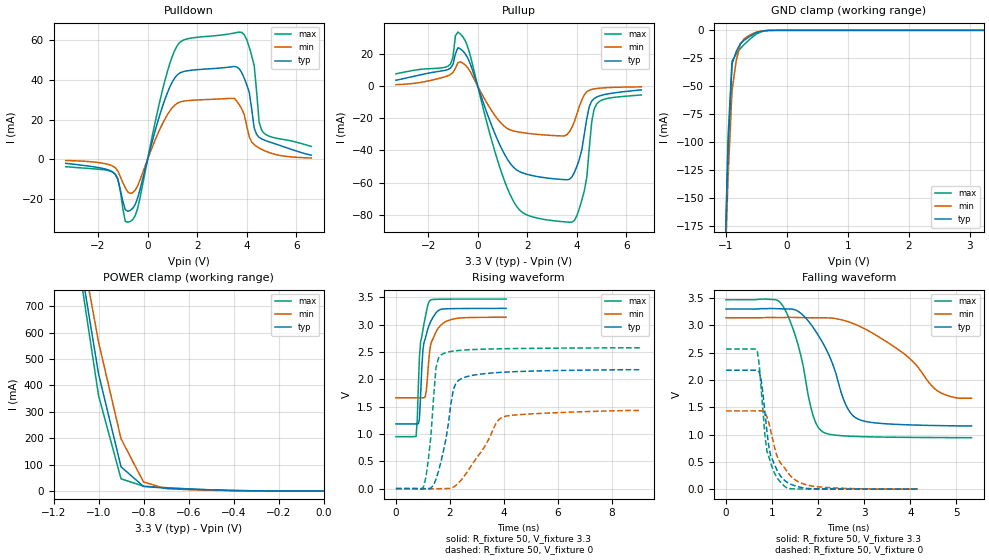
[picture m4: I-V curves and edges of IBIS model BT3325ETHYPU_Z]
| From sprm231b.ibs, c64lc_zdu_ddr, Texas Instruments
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|   Model Cell BT3325ETHYPUFZSCP18
[Model]   BT3325ETHYPU_Z
Model_type   I/O
Polarity   Non-Inverting
Enable   Active-Low
Vinl =  0.8V
Vinh =  2V
Cref =  15.0000pF
Rref =  100.0000M
Vref =  0V
Vmeas =  1.65
C_comp   2.566034p   2.494321p   2.623693p
[Model Spec]
Vinl   0.8V   0.8V   0.8V
Vinh   2V   2V   2V
[Temperature Range]   25   125   -40
[Voltage Range]   3.3   3.14   3.47
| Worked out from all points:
|   slope of the pulldown table from 0 to 0.495 V, typ, clamps not added: 22 ohm
|   slope of the pullup table from 0 to 0.495 V, typ, clamps not added: 22.7 ohm
|   GND clamp passes 1 mA (typ) near -0.43 V on its own axis
|   POWER clamp passes 1 mA (typ) near -0.34 V on its own axis
|   rising waveform, R_fixture 50, V_fixture 3.3: 20-80 % time 251ps typ, 305ps min, 218ps max; typ from 1.18 V to 3.3 V
|   rising waveform, R_fixture 50, V_fixture 0: 20-80 % time 464ps typ, 1.04ns min, 263ps max; typ from 0 V to 2.18 V
|   falling waveform, R_fixture 50, V_fixture 3.3: 20-80 % time 617ps typ, 1.19ns min, 415ps max; typ from 3.3 V to 1.16 V
|   falling waveform, R_fixture 50, V_fixture 0: 20-80 % time 257ps typ, 407ps min, 215ps max; typ from 2.18 V to 0.001 V
[POWER_clamp]
|   voltage   I(typ)   I(min)   I(max)
-3.3V     15.08A     13.67A     16.19A
-1.067V   791.8mA    876.7mA    739.6mA
-1.033V   617.9mA    720.5mA    550.7mA
-1V       443.9mA    564.3mA    361.8mA
-900mV    91.43mA    197.6mA    46.01mA
-800mV    17.02mA    33.96mA    17.85mA
-700mV    10.54mA    8.637mA    12.45mA
-400mV    1.692mA    1.038mA    1.485mA
-11.55fV  124.8nA    283.5nA    244.8nA
[Pulldown]
|   voltage   I(typ)   I(min)   I(max)
-3.3V     -2.009mA   -598.7uA   -3.704mA
-1.4V     -6.443mA   -3.405mA   -6.53mA
-900mV    -25.27mA   -14.31mA   -31.18mA
-600mV    -24.63mA   -16.76mA   -30.27mA
700mV     30.19mA    20.31mA    39.68mA
1.2V      42.48mA    28.23mA    57.23mA
3.7V      45.45mA    27.48mA    63.96mA
4.1V      33.69mA    11.27mA    56.39mA
4.3V      15.66mA    7.38mA     47.1mA
4.5V      11.07mA    5.671mA    18.53mA
4.6V      10.27mA    5.02mA     14.66mA
6.6V      2.127mA    698uA      6.501mA
[Pullup]
|   voltage   I(typ)   I(min)   I(max)
-3.3V     3.672mA    942uA      7.701mA
-1.2V     10.36mA    6.515mA    12.43mA
-900mV    20.11mA    11.14mA    31.42mA
-700mV    23.22mA    15.14mA    32.51mA
1.4V      -49.76mA   -27.7mA    -70.44mA
3.4V      -58.08mA   -30.96mA   -84.31mA
4.1V      -45.46mA   -12.4mA    -76.1mA
4.4V      -20.13mA   -3.457mA   -56.69mA
4.5V      -12.6mA    -2.531mA   -38.48mA
4.6V      -9.27mA    -2.014mA   -21.88mA
4.8V      -6.737mA   -1.451mA   -11.02mA
6.6V      -2.305mA   -414.2uA   -5.467mA
[GND_clamp]
|   voltage   I(typ)   I(min)   I(max)
-3.3V     -17.31A    -15.67A    -18.52A
-1.033V   -242.4mA   -247.8mA   -249mA
-966.7mV  -107.5mA   -133.2mA   -96.03mA
-900mV    -30.1mA    -53.58mA   -27.5mA
-833.3mV  -19.23mA   -27.87mA   -21.45mA
-766.7mV  -12.15mA   -12.5mA    -16.49mA
-700mV    -8.877mA   -7.487mA   -12.64mA
-566.7mV  -4.001mA   -3.142mA   -6.073mA
-500mV    -2.028mA   -1.615mA   -3.281mA
-433.3mV  -975.8uA   -827.9uA   -1.629mA
-300mV    -52.39uA   -75.47uA   -82.68uA
3.233V    68.23nA    4.314uA    201.3nA
[Ramp]
| variable   typ   min   max
dV/dt_f   1.303669/0.626078n   0.9851965/1.278608n   1.530191/0.4190725n
dV/dt_r   1.326854/0.4645258n  0.9114419/1.09422n   1.556718/0.2523652n
R_load = 50
[Rising Waveform]
R_fixture = 50
V_fixture = 3.3
V_fixture_min = 3.14
V_fixture_max = 3.47
|   time   V(typ)   V(min)   V(max)
0s        1.183V     1.662V     951mV
748ps     1.185V     1.663V     955.3mV
792ps     1.185V     1.663V     1.275V
872ps     1.279V     1.664V     2.417V
916ps     1.714V     1.664V     2.694V
1ns       2.535V     1.663V     2.907V
1.124ns   2.817V     1.777V     3.227V
1.252ns   3.016V     2.527V     3.44V
1.876ns   3.292V     3.063V     3.469V
4.084ns   3.299V     3.137V     3.47V
[Rising Waveform]
R_fixture = 50
V_fixture = 0
V_fixture_min = 0
V_fixture_max = 0
|   time   V(typ)   V(min)   V(max)
0s        45.31uV    38.64uV    55.69uV
1.016ns   -6.992mV   17.43uV    21.41mV
1.112ns   -3.502mV   -2.537mV   207.8mV
1.296ns   9.616mV    -6.223mV   961.8mV
1.484ns   168.6mV    -2.402mV   2.211V
1.76ns    684.9mV    -53.96uV   2.473V
2.132ns   1.82V      27.37mV    2.518V
2.504ns   2.03V      210.4mV    2.536V
3.992ns   2.131V     1.314V     2.561V
9.096ns   2.176V     1.431V     2.578V
[Falling Waveform]
R_fixture = 50
V_fixture = 3.3
V_fixture_min = 3.14
V_fixture_max = 3.47
|   time   V(typ)   V(min)   V(max)
0s        3.3V       3.14V      3.47V
1.192ns   3.304V     3.143V     3.405V
1.572ns   3.253V     3.144V     2.619V
1.896ns   2.956V     3.141V     1.33V
2.116ns   2.655V     3.139V     1.041V
2.604ns   1.537V     3.079V     974.4mV
2.82ns    1.304V     3.013V     966.1mV
3.908ns   1.18V      2.45V      949.2mV
4.612ns   1.165V     1.788V     945.1mV
5.328ns   1.159V     1.665V     943.4mV
[Falling Waveform]
R_fixture = 50
V_fixture = 0
V_fixture_min = 0
V_fixture_max = 0
|   time   V(typ)   V(min)   V(max)
0s        2.18V      1.434V     2.567V
676ps     2.181V     1.434V     2.539V
760ps     2.015V     1.436V     1.867V
844ps     1.408V     1.399V     986.7mV
888ps     1.055V     1.328V     696.1mV
972ps     602mV      1.062V     472.7mV
1.1ns     359.9mV    624.7mV    221.2mV
1.272ns   160mV      388.9mV    51.79mV
1.864ns   8.981mV    58.08mV    1.916mV
4.168ns   936.9uV    3.182mV    81.56uV
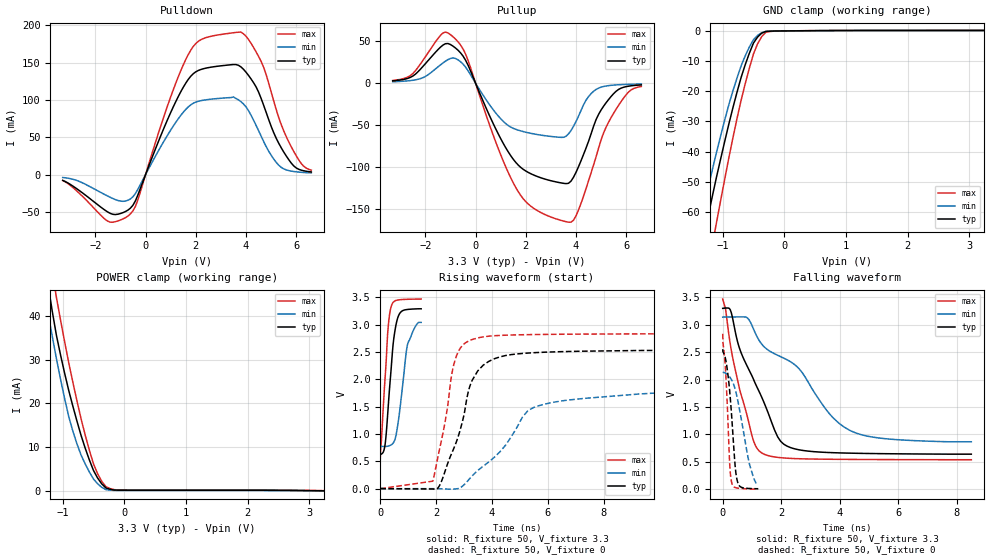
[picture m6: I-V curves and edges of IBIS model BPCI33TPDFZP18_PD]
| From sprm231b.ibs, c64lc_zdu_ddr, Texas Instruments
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|   Model Cell BPCI33TPDFZP18
[Model]   BPCI33TPDFZP18_PD
Model_type   I/O
Polarity   Non-Inverting
Enable   Active-Low
Vinl =  0.8
Vinh =  2.0
Cref =  10.0000pF
Rref =  50.0000
Vref =  1.5V
Vmeas =  1.5
C_comp   3.400798p   3.348868p   3.529696p
[Temperature Range]   25   125   -40
[Voltage Range]   3.3   3.14   3.47
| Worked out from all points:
|   slope of the pulldown table from 0 to 0.495 V, typ, clamps not added: 11.5 ohm
|   slope of the pullup table from 0 to 0.495 V, typ, clamps not added: 14.2 ohm
|   GND clamp passes 1 mA (typ) near -0.38 V on its own axis
|   POWER clamp passes 1 mA (typ) near -0.32 V on its own axis
|   rising waveform, R_fixture 50, V_fixture 3.3: 20-80 % time 251ps typ, 312ps min, 203ps max; typ from 0.618 V to 3.29 V
|   rising waveform, R_fixture 50, V_fixture 0: 20-80 % time 912ps typ, 3.25ns min, 574ps max; typ from 0 V to 2.55 V
|   falling waveform, R_fixture 50, V_fixture 3.3: 20-80 % time 1.24ns typ, 2.46ns min, 739ps max; typ from 3.3 V to 0.642 V
|   falling waveform, R_fixture 50, V_fixture 0: 20-80 % time 223ps typ, 423ps min, 145ps max; typ from 2.56 V to 0.011 V
[POWER_clamp]
|   voltage   I(typ)   I(min)   I(max)
-3.3V     267mA      206.5mA    325.9mA
-1.3V     53.32mA    45.7mA     64.06mA
-1.233V   46.92mA    40.45mA    56.76mA
-1.167V   41mA       35.29mA    50.15mA
-1.1V     35.56mA    30.24mA    44.25mA
-900mV    22.94mA    16.96mA    29.27mA
-700mV    12.65mA    8.17mA     16.44mA
-500mV    4.676mA    2.728mA    6.199mA
-366.7mV  1.613mA    815.6uA    2.199mA
-300mV    677.7uA    289.8uA    976.9uA
-100mV    146.2uA    88.28uA    203.6uA
3.233V    6.454uA    -18.59uA   49.21uA
[Pulldown]
|   voltage   I(typ)   I(min)   I(max)
-3.3V     -7.788mA   -3.889mA   -7.987mA
-1.5V     -50.3mA    -28.94mA   -62.59mA
-700mV    -47.57mA   -34.42mA   -55.53mA
-400mV    -34.9mA    -25.14mA   -42.3mA
900mV     75.57mA    54.22mA    94.65mA
1.8V      131.8mA    93.47mA    166.8mA
2.4V      142.6mA    100.2mA    183.5mA
3.8V      144.2mA    97.66mA    191mA
4.6V      102.2mA    51.63mA    151.8mA
5.3V      42.12mA    12.63mA    76.7mA
6.1V      7.063mA    3.322mA    19.68mA
6.6V      3.543mA    2.233mA    5.963mA
[Pullup]
|   voltage   I(typ)   I(min)   I(max)
-3.3V     2.841mA    1.735mA    3.327mA
-2.6V     6.94mA     3.146mA    9.053mA
-1.4V     43.04mA    21.89mA    57.16mA
-1V       46.23mA    29.6mA     58.04mA
-400mV    27.62mA    19.3mA     34.95mA
900mV     -60.4mA    -39.07mA   -77.82mA
1.7V      -97.84mA   -56.07mA   -129.6mA
3.7V      -119.6mA   -60.58mA   -166mA
4.1V      -99.72mA   -39.32mA   -151.4mA
5.2V      -23.22mA   -3.285mA   -52.37mA
6V        -4.027mA   -1.402mA   -13.57mA
6.6V      -2.032mA   -942.8uA   -3.85mA
[GND_clamp]
|   voltage   I(typ)   I(min)   I(max)
-3.3V     -301.2mA   -235.6mA   -364.4mA
-1.367V   -75.51mA   -63.63mA   -93.99mA
-1.3V     -68.15mA   -57.67mA   -85.99mA
-1.233V   -61.35mA   -51.8mA    -78.43mA
-1.1V     -48.52mA   -40.32mA   -63.59mA
-900mV    -30.93mA   -24.51mA   -42.17mA
-700mV    -15.41mA   -11.59mA   -22.96mA
-500mV    -4.036mA   -2.901mA   -7.657mA
-366.7mV  -757uA     -601.1uA   -1.906mA
-300mV    -173.8uA   -161.6uA   -469.5uA
-166.7mV  -45.04uA   -35.14uA   -70.3uA
3.233V    143uA      89.63uA    196.9uA
[Ramp]
| variable   typ   min   max
dV/dt_f   1.61157/1.246779n   1.412395/2.561021n   1.763671/0.7410372n
dV/dt_r   1.538377/0.9052153n   1.251512/3.825666n   1.705345/0.5758693n
R_load = 50
[Rising Waveform]
R_fixture = 50
V_fixture = 3.3
V_fixture_min = 3.14
V_fixture_max = 3.47
|   time   V(typ)   V(min)   V(max)
0s        617.6mV    771.4mV    534.9mV
8ps       625.1mV    771.6mV    684.2mV
176ps     820.5mV    771.5mV    2.052V
280ps     1.469V     777.4mV    2.937V
384ps     2.156V     798.4mV    3.319V
488ps     2.76V      854.5mV    3.419V
656ps     3.165V     1.268V     3.45V
976ps     3.276V     2.635V     3.462V
1.264ns   3.286V     2.971V     3.465V
1.464ns   3.288V     3.039V     3.466V
[Rising Waveform]
R_fixture = 50
V_fixture = 0
V_fixture_min = 0
V_fixture_max = 0
|   time   V(typ)   V(min)   V(max)
0s        22.7uV     15.94uV    32.12uV
1.88ns    -6.279mV   -641.8uV   136.8mV
2.12ns    55.12mV    -1.771mV   715.9mV
2.672ns   785.6mV    -5.519mV   2.342V
3.184ns   1.834V     172.6mV    2.704V
3.488ns   2.151V     331.2mV    2.756V
4.488ns   2.434V     796.2mV    2.805V
5.288ns   2.479V     1.428V     2.815V
6.496ns   2.504V     1.604V     2.823V
26.97ns   2.552V     2.038V     2.835V
[Falling Waveform]
R_fixture = 50
V_fixture = 3.3
V_fixture_min = 3.14
V_fixture_max = 3.47
|   time   V(typ)   V(min)   V(max)
0s        3.298V     3.139V     3.468V
96ps      3.305V     3.141V     3.293V
264ps     3.266V     3.141V     2.629V
568ps     2.582V     3.144V     1.846V
1.056ns   2.002V     2.92V      881.9mV
1.328ns   1.687V     2.652V     666.3mV
2.088ns   823.7mV    2.392V     572mV
2.616ns   720.2mV    2.196V     558.1mV
4.36ns    659.7mV    1.071V     545.7mV
8.504ns   641.6mV    867.6mV    539.9mV
[Falling Waveform]
R_fixture = 50
V_fixture = 0
V_fixture_min = 0
V_fixture_max = 0
|   time   V(typ)   V(min)   V(max)
0s        2.555V     2.134V     2.835V
8ps       2.507V     2.133V     2.668V
88ps      2.398V     2.12V      2.24V
160ps     2.168V     2.095V     1.495V
240ps     1.781V     2.049V     454.5mV
304ps     1.351V     1.995V     132mV
424ps     434.4mV    1.827V     33.66mV
520ps     116mV      1.607V     21.52mV
912ps     16.25mV    467.6mV    7.166mV
1.216ns   11.47mV    102.8mV    3.42mV
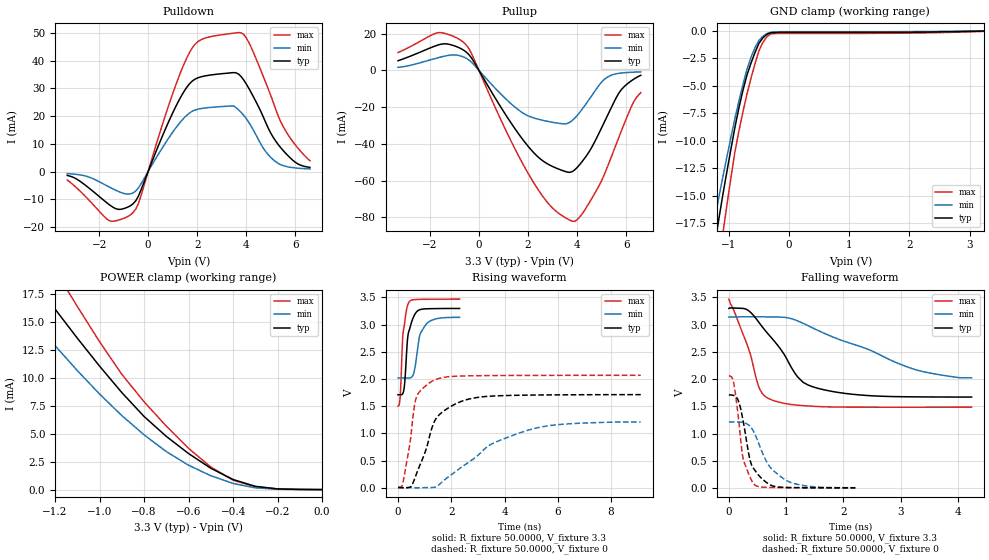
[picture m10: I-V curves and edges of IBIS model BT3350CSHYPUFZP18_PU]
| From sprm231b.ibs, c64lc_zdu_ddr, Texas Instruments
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|   Model Cell BT3350CSHYPUFZP18
[Model]   BT3350CSHYPUFZP18_PU
Model_type   I/O
Polarity   Non-Inverting
Enable   Active-Low
Vinl =  0.8V
Vinh =  2V
Cref =  15.0000pF
Rref =  100.0000M
Vref =  0V
Vmeas =  1.65
C_comp   1.705749p   1.660791p   1.75003p
[Model Spec]
Vinl   0.8V   0.8V   0.8V
Vinh   2V   2V   2V
[Temperature Range]   25   125   -40
[Voltage Range]   3.3   3.14   3.47
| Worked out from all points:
|   slope of the pulldown table from 0 to 0.495 V, typ, clamps not added: 45.1 ohm
|   slope of the pullup table from 0 to 0.495 V, typ, clamps not added: 43.8 ohm
|   GND clamp passes 1 mA (typ) near -0.48 V on its own axis
|   POWER clamp passes 1 mA (typ) near -0.41 V on its own axis
|   rising waveform, R_fixture 50.0000, V_fixture 3.3: 20-80 % time 204ps typ, 282ps min, 155ps max; typ from 1.71 V to 3.3 V
|   rising waveform, R_fixture 50.0000, V_fixture 0: 20-80 % time 850ps typ, 2.32ns min, 380ps max; typ from 0.003 V to 1.71 V
|   falling waveform, R_fixture 50.0000, V_fixture 3.3: 20-80 % time 671ps typ, 1.55ns min, 359ps max; typ from 3.3 V to 1.67 V
|   falling waveform, R_fixture 50.0000, V_fixture 0: 20-80 % time 218ps typ, 400ps min, 164ps max; typ from 1.71 V to 0.006 V
[POWER_clamp]
|   voltage   I(typ)   I(min)   I(max)
-3.3V     84.32mA    63.21mA    102.6mA
-1.4V     21.71mA    17.52mA    26.37mA
-1.367V   20.75mA    16.74mA    25.23mA
-1.233V   17.03mA    13.62mA    20.73mA
-1.133V   14.39mA    11.37mA    17.45mA
-900mV    8.665mA    6.611mA    10.3mA
-800mV    6.531mA    4.891mA    7.85mA
-600mV    3.22mA     2.176mA    3.684mA
-500mV    1.907mA    1.239mA    2.016mA
-400mV    899.8uA    551.4uA    840.8uA
-300mV    293.2uA    156uA      256.6uA
0V        111.9nA    201.5nA    235.4nA
[Pulldown]
|   voltage   I(typ)   I(min)   I(max)
-3.3V     -1.414mA   -745.4uA   -3.05mA
-1.6V     -11.86mA   -5.525mA   -17.66mA
-700mV    -12.23mA   -8.019mA   -15.5mA
-400mV    -8.953mA   -5.978mA   -11.65mA
900mV     19.23mA    12.9mA     25.53mA
1.7V      31.81mA    21.22mA    43.17mA
2.2V      34.3mA     22.8mA     47.78mA
3.7V      35.12mA    22.19mA    50.19mA
4.1V      30.16mA    17.85mA    46.74mA
5.1V      12.38mA    4.294mA    25.08mA
5.7V      5.756mA    1.687mA    13.38mA
6.6V      1.491mA    938uA      3.886mA
[Pullup]
|   voltage   I(typ)   I(min)   I(max)
-3.3V     5.279mA    1.68mA     9.743mA
-1.7V     13.72mA    6.799mA    20.48mA
-600mV    10.83mA    7.151mA    14.99mA
1.3V      -28.42mA   -18.04mA   -38.22mA
2.2V      -44.3mA    -25.71mA   -60.41mA
3V        -52.29mA   -28.23mA   -74.9mA
3.8V      -55.14mA   -27.3mA    -82.11mA
4.3V      -48.01mA   -19.44mA   -76.32mA
5.2V      -25.74mA   -3.981mA   -53.86mA
5.8V      -10.57mA   -1.414mA   -33.26mA
6.3V      -4.87mA    -940.5uA   -17.38mA
6.6V      -2.661mA   -794.2uA   -12.11mA
[GND_clamp]
|   voltage   I(typ)   I(min)   I(max)
-3.3V     -100.5mA   -76.68mA   -120mA
-1.3V     -21.87mA   -18.97mA   -26.4mA
-1.233V   -19.47mA   -17.07mA   -23.74mA
-1.167V   -17.17mA   -15.19mA   -21.1mA
-1.1V     -14.95mA   -13.32mA   -18.48mA
-1.033V   -12.86mA   -11.51mA   -15.92mA
-900mV    -8.833mA   -8.012mA   -11.06mA
-700mV    -4.051mA   -3.523mA   -5.792mA
-500mV    -1.133mA   -857.3uA   -1.811mA
-366.7mV  -308.6uA   -237uA     -524.5uA
-166.7mV  -140.1uA   -73.15uA   -228.2uA
3.233V    -8.683uA   9.95uA     -45.02uA
[Ramp]
| variable   typ   min   max
dV/dt_f  0.9828108/0.6678639n  0.7311943/1.730842n   1.197706/0.3608563n
dV/dt_r   1.030688/0.8545153n  0.7443786/2.444011n   1.242133/0.3789795n
R_load = 50
[Rising Waveform]
R_fixture = 50.0000
V_fixture = 3.3
V_fixture_min = 3.14
V_fixture_max = 3.47
|   time   V(typ)   V(min)   V(max)
0s        1.71V      2.018V     1.5V
80ps      1.71V      2.019V     1.671V
168ps     1.724V     2.019V     2.701V
224ps     1.815V     2.019V     2.953V
352ps     2.709V     2.019V     3.343V
400ps     2.867V     2.019V     3.405V
592ps     3.152V     2.111V     3.459V
800ps     3.271V     2.766V     3.464V
1.04ns    3.29V      2.997V     3.466V
2.312ns   3.298V     3.134V     3.469V
[Rising Waveform]
R_fixture = 50.0000
V_fixture = 0
V_fixture_min = 0
V_fixture_max = 0
|   time   V(typ)   V(min)   V(max)
0s        3.179mV    1.918mV    4.458mV
200ps     -2.005mV   1.924mV    130.7mV
496ps     27mV       627.6uV    1.01V
672ps     229.1mV    -2.315mV   1.638V
1.36ns    1.211V     7.009mV    1.979V
1.728ns   1.415V     136.8mV    2.03V
2.552ns   1.616V     434.7mV    2.057V
3.512ns   1.685V     804.2mV    2.063V
4.736ns   1.702V     1.036V     2.066V
9.12ns    1.712V     1.208V     2.068V
[Falling Waveform]
R_fixture = 50.0000
V_fixture = 3.3
V_fixture_min = 3.14
V_fixture_max = 3.47
|   time   V(typ)   V(min)   V(max)
0s        3.3V       3.14V      3.47V
352ps     3.252V     3.145V     2.534V
536ps     3.027V     3.145V     1.825V
712ps     2.798V     3.143V     1.636V
920ps     2.528V     3.139V     1.568V
1.2ns     2.044V     3.071V     1.523V
1.48ns    1.855V     2.933V     1.502V
2.224ns   1.717V     2.625V     1.487V
3.208ns   1.676V     2.191V     1.486V
4.24ns    1.672V     2.026V     1.487V
[Falling Waveform]
R_fixture = 50.0000
V_fixture = 0
V_fixture_min = 0
V_fixture_max = 0
|   time   V(typ)   V(min)   V(max)
0s        1.711V     1.215V     2.066V
88ps      1.7V       1.216V     1.912V
176ps     1.576V     1.214V     1.206V
224ps     1.368V     1.209V     716.6mV
256ps     1.196V     1.202V     512.3mV
368ps     523.4mV    1.137V     205.6mV
456ps     326.4mV    988.6mV    56.27mV
704ps     71.12mV    408.9mV    13.29mV
1.024ns   12.35mV    130.2mV    8.266mV
2.208ns   5.569mV    8.251mV    5.289mV
